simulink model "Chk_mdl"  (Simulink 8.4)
settings: Solver=ode45  StartTime=0.0  StopTime=10.0  MaxStep=1e-3  MinStep=1e-4  RelTol=1e-3
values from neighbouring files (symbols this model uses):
  g = 9.8    [FurikoSlvCheck.m]    (also in mfuriko.m)
  k = k+1    (= 2)    [while_break.m]    (also in FurikoSlvCheck.m = 0.2)
  l = 2    [FurikoSlvCheck.m]
  m = 1    [FurikoSlvCheck.m]

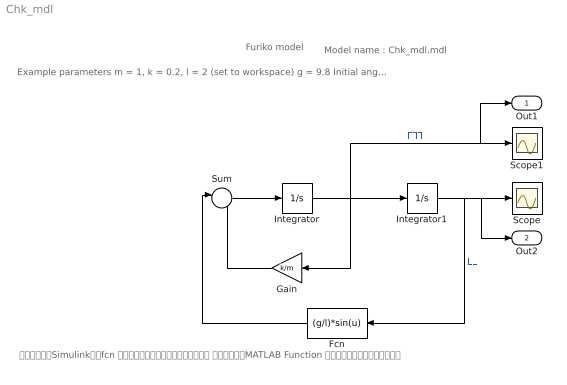
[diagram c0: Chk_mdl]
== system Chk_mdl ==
  note: 注意）最新のSimulinkではfcn ブロックの使用を推奨していません． したがって，MATLAB Function ブロックに変更してください．
  note: Model name : Chk_mdl.mdl
  note: Example parameters m = 1, k = 0.2, l = 2 (set to workspace) g = 9.8 Initial angle : 1 rad (set to integrator1 block)
  note: Furiko model
  Fcn : Fcn  Expr=(g/l)*sin(u)
  Gain : Gain  Gain=k/m
  Integrator : Integrator
  Integrator1 : Integrator  InitialCondition=1
  Scope : Scope
  Scope1 : Scope
  Sum : Sum  Inputs=|--
  Out1 : Outport
  Out2 : Outport  Port=2
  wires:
  Fcn/1 -> Sum/1
  Gain/1 -> Sum/2
  Sum/1 -> Integrator/1
  Integrator/1 -> Out1/1, Scope1/1, Gain/1, Integrator1/1  "角速度"
  Integrator1/1 -> Fcn/1, Out2/1, Scope/1  "角度"
